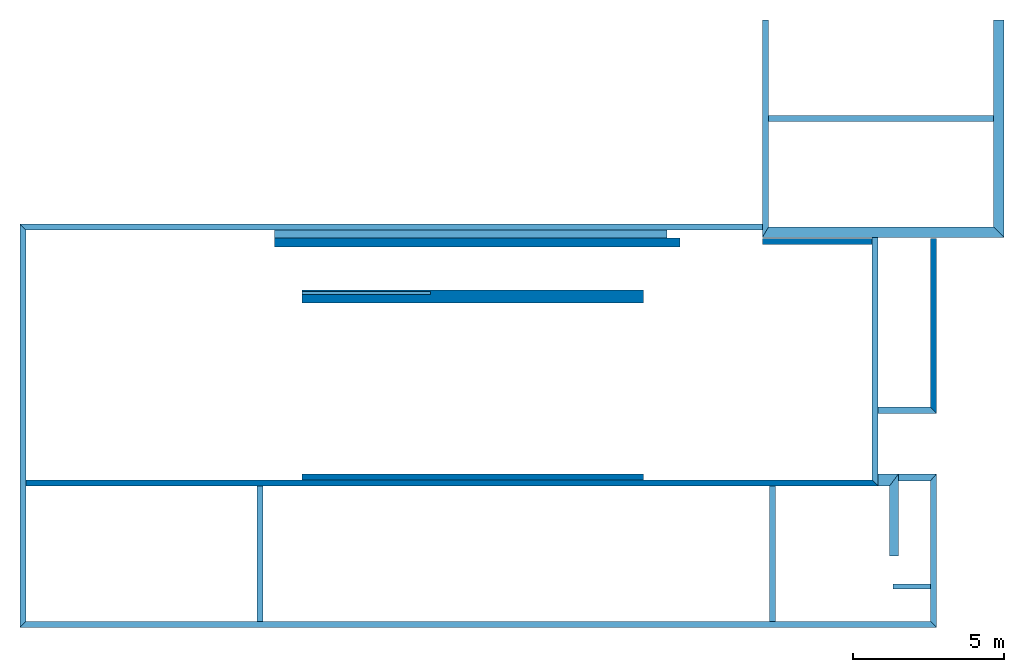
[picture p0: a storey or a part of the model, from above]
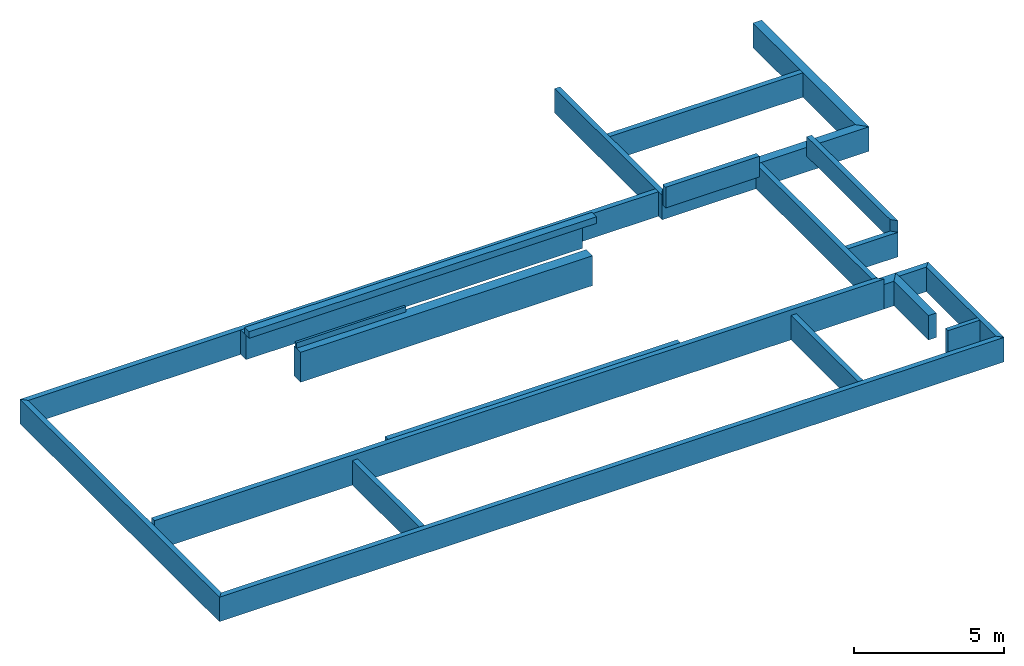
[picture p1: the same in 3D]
Properties of the parts of a building model (IFC2X3)

# File
Description: ViewDefinition [CoordinationView_V2.0], Option [Elements to export: Entire project], Option [Partial Structure Display: Entire Model], Option [IFC Domain: All], Option [Structural Function: All Elements], Option [Convert Grid elements: On], Option [Convert IFC Annotations and ARCHICAD 2D elements: Off], Option [Convert 2D symbols of Doors and Windows: Off], Option [Export geometries that Participates in Collision Detection only: Off], Option [Split complex elements: Off], Option [Material Preservation: Explode where necessary], Option [Elements in Solid Element Operations: Extruded/revolved], Option [Elements with junctions: Extruded/revolved without junctions], Option [IFC Model position: Survey Point and Project Origin], Option [Curtain Wall export mode: Container Element], Option [Railing export mode: Single Element], Option [Stair export mode: Container Element], Option [Properties To Export: All properties], Option [Space containment: Off], Option [Bounding Box: Off], Option [Geometry to type objects: Off], Option [Element Properties: Off], Option [Building Material Properties: Off], Option [Element Parameters: Off], Option [Component Parameters: Off], Option [IFC Base Quantities: Off], Option [Door Window Parameters: Off], Option [IFC Space boundaries: Off], Option [ARCHICAD Zone Categories as IFC Space classification data: Off], Option [Element Classifications: On]
File name: /Users/adquat/Desktop/SAUV/9 EGLISE SDFPRO DCE.ifc
Time: 2024-02-08T12:19:42
Author: (nom de l'architecte)
Organization: (Atelier d'architecture.... )
Written by: The EXPRESS Data Manager Version 5.02.0100.09 : 18 Aug 2016
Made in: IFC file generated by GRAPHISOFT ARCHICAD 25.0.0 FRA FULL Macintosh version (IFC add-on version: 4013 FRA FULL).
Authorization: (nom de l'architecte)

# IfcProject, SALLE DES FÈTES DE NEUF ÉGLISE
Phase: EDL

# IfcSite, Site
RefLatitude: 48, 52, 0, 0; RefLongitude: 2, 20, 0, 0; RefElevation: 0 m

# IfcBuildingStorey (4)
In: Bâtiment
Name | Elevation (m)
VIDE SANITAIRE | -1
RDC | -5.32907e-15
PLAFOND | 4
TOITURE | 7.4

# IfcSpace: 9 Communication & Accès (16)
In: RDC
InteriorOrExteriorSpace: INTERNAL; Classification: Espace (Classification ARCHICAD)
AC_Pset_RenovationAndPhasing - Renovation Status: Existing
Name (Plafond:...) | LongName
 Dalles | VESTIAIRE
 Dalles | SALLE PRINCIPALE
 Dalles | ACCUEIL
 Ba CF1h | RANGEMENT
 Dalles | DGT.
 BA cf1h | L. TECH.-REGIE
 Ba CF1H | STOCKAGE
 Dalles | SAN. H
 Dalles | Mixte PMR
 Dalles | DEGT.
 Dalles | Public PMR
 Dalles | CUISINE
 Dalles | L.Tech
 Dalles | SAN. F
 Dalles | BUVETTE
 Dalles

# IfcBuildingElementPart (10)
In: RDC
Name | Material
5 x Plâtre lissé 291446788 | Plâtre lissé 291446788
5 x Isolation laine de pierre 378182646 | Isolation laine de pierre 378182646

# IfcBuildingElementProxy: IfcBuildingElementProxy, MARCHE-012
In: RDC
Material: Bois 390117389
AC_Pset_RenovationAndPhasing - Renovation Status: New

# IfcBuildingElementProxy: Type d'escalier, ESCALIER-003
In: RDC
AC_Pset_RenovationAndPhasing - Renovation Status: New

# IfcColumn: Diagonales 1167258944 150 x 150 (2)
In: RDC
Classification: Poteau (Classification ARCHICAD); Material: Diagonales 1167258944
AC_Pset_RenovationAndPhasing - Renovation Status: New
Pset_ColumnCommon - LoadBearing: yes; IsExternal: no; Reference: Diagonales 1167258944 150 x 150

# IfcColumn: Diagonales 1167258944 200 x 200 (2)
In: RDC
Classification: Poteau (Classification ARCHICAD); Material: Diagonales 1167258944
Pset_ColumnCommon - LoadBearing: yes; IsExternal: no; Reference: Diagonales 1167258944 200 x 200
Name | Renovation Status
Pot-003 | To Be Demolished
Pot-002 | New

# IfcColumn: Diagonales 1167258944 D180 (3)
In: RDC
Classification: Poteau (Classification ARCHICAD); Material: Diagonales 1167258944
AC_Pset_RenovationAndPhasing - Renovation Status: To Be Demolished
Pset_ColumnCommon - LoadBearing: yes; IsExternal: no; Reference: Diagonales 1167258944 D180

# IfcDiscreteAccessory: Chevron simple 25 (15)
In: TOITURE
Classification: Accessoire distinct (Classification ARCHICAD); Material: Béton 2389403790
AC_Pset_RenovationAndPhasing - Renovation Status: New

# IfcDiscreteAccessory: Panne 25 (28)
In: TOITURE
Classification: Accessoire distinct (Classification ARCHICAD); Material: Béton 2389403790
AC_Pset_RenovationAndPhasing - Renovation Status: New
Name
14 x Protection-014
14 x Protection-012

# IfcDiscreteAccessory: Poteau 1 25 (7)
In: TOITURE
Classification: Accessoire distinct (Classification ARCHICAD); Material: Béton 2389403790
AC_Pset_RenovationAndPhasing - Renovation Status: New

# IfcDistributionElement: Evier à double bacs 25 (2)
In: RDC
Classification: Élément de distribution (Classification ARCHICAD)
Name | Renovation Status
Protection-003 | Existing
Protection-003 | New

# IfcDistributionElement: Lavabo 25, Protection-011
In: RDC
Classification: Élément de distribution (Classification ARCHICAD)
AC_Pset_RenovationAndPhasing - Renovation Status: New

# IfcDistributionElement: Lavabo d'angle 25 (2)
In: RDC
Classification: Élément de distribution (Classification ARCHICAD)
AC_Pset_RenovationAndPhasing - Renovation Status: New

# IfcDistributionElement: Plan multi vasques 25, Protection-011
In: RDC
Classification: Élément de distribution (Classification ARCHICAD)
AC_Pset_RenovationAndPhasing - Renovation Status: New

# IfcDistributionElement: Urinoir 25 (2)
In: RDC
Classification: Élément de distribution (Classification ARCHICAD)
AC_Pset_RenovationAndPhasing - Renovation Status: New

# IfcDistributionElement: WC 25 (4)
In: RDC
Classification: Élément de distribution (Classification ARCHICAD)
AC_Pset_RenovationAndPhasing - Renovation Status: New

# IfcDoor: Porte 25 (5)
In: RDC
Type - OperationType: SINGLE_SWING_LEFT; ParameterTakesPrecedence: no; Sizeable: no
Classification: Porte (Classification ARCHICAD)
Name | OverallHeight (m) | OverallWidth (m) | Renovation Status
Por-004 | 2.1 | 0.91 | New
Por-004 | 2.1 | 1.086 | New
Por-005 | 2.13 | 0.91 | Existing
Por-004 | 2.118 | 0.886 | New
Por-004 | 2.1 | 0.596 | New

# IfcDoor: Porte 25 (7)
In: RDC
Type - OperationType: SINGLE_SWING_RIGHT; ParameterTakesPrecedence: no; Sizeable: no
Classification: Porte (Classification ARCHICAD)
AC_Pset_RenovationAndPhasing - Renovation Status: New
Name | OverallHeight (m) | OverallWidth (m)
Por-004 | 2.1 | 0.8
Por-004 | 2.1 | 0.886
2 x Por-004 | 2.1 | 1.086
Por-006 | 2.1 | 0.6
Por-006 | 2.1 | 0.733967
Por-004 | 2.118 | 0.886

# IfcDoor: Porte avec imposte 25, Por-004
In: RDC
Type - OperationType: SINGLE_SWING_RIGHT; ParameterTakesPrecedence: no; Sizeable: no
OverallHeight: 2.5 m; OverallWidth: 1.03 m; Classification: Porte (Classification ARCHICAD)
AC_Pset_RenovationAndPhasing - Renovation Status: New

# IfcDoor: Porte double 25 (2)
In: RDC
Type - OperationType: DOUBLE_DOOR_SINGLE_SWING; ParameterTakesPrecedence: no; Sizeable: no
Classification: Porte (Classification ARCHICAD)
AC_Pset_RenovationAndPhasing - Renovation Status: Existing
Name | OverallHeight (m) | OverallWidth (m)
Por-006 | 2.1 | 1.8
Por-006 | 2.5 | 2.34

# IfcDoor: Porte double asymétrique 25, Por-006
In: RDC
Type - OperationType: DOUBLE_DOOR_DOUBLE_SWING; ParameterTakesPrecedence: no; Sizeable: no
OverallHeight: 2.1 m; OverallWidth: 1.48 m; Classification: Porte (Classification ARCHICAD)
AC_Pset_RenovationAndPhasing - Renovation Status: New

# IfcDoor: Porte double asymétrique 25 (5)
In: RDC
Type - OperationType: DOUBLE_DOOR_SINGLE_SWING; ParameterTakesPrecedence: no; Sizeable: no
Classification: Porte (Classification ARCHICAD)
AC_Pset_RenovationAndPhasing - Renovation Status: New
Name | OverallHeight (m) | OverallWidth (m)
Por-006 | 2.1 | 1.5
2 x Por-006 | 2.1 | 1.47
Por-006 | 2.1 | 1.4
Por-006 | 2.15 | 1.3

# IfcFurnishingElement: Cuisinière gaz 25, Protection-003
In: RDC
Classification: Mobilier (Classification ARCHICAD)
AC_Pset_RenovationAndPhasing - Renovation Status: Existing

# IfcSlab: 50 % 1167783752 28, Dalle-16
In: RDC
Type - PredefinedType: FLOOR
Classification: Dalle (Classification ARCHICAD); Material: 50 % 1167783752 0.028 m
AC_Pset_RenovationAndPhasing - Renovation Status: New

# IfcSlab: 50 % 1167783752 30 (3)
In: RDC
Type - PredefinedType: FLOOR
Classification: Dalle (Classification ARCHICAD); Material: 50 % 1167783752 0.03 m
AC_Pset_RenovationAndPhasing - Renovation Status: New

# IfcSlab: 50 % 1167783752 50 (6)
In: RDC
Type - PredefinedType: FLOOR
Classification: Dalle (Classification ARCHICAD); Material: 50 % 1167783752 0.05 m
AC_Pset_RenovationAndPhasing - Renovation Status: New
Name
3 x Dalle-13
Dalle-17
2 x Dalle-16

# IfcSlab: Dalle: Etancheite bicouche auto protegee + iso22 375 (3)
In: TOITURE
Type - PredefinedType: FLOOR
Classification: Dalle (Classification ARCHICAD); Material: Fer 269029580 0.005 m, Etanchéité 286798990 0.005 m, 25 % 7019220 0.005 m, Isolation laine de pierre 356123750 0.15 m, 50 % 1167783752 0.005 m, Sans Trame 1167258944 0.005 m, Bois massif 333501804 0.2 m
AC_Pset_RenovationAndPhasing - Renovation Status: New

# IfcSlab: Diagonales 1167258944 200 (2)
In: RDC
Type - PredefinedType: FLOOR
Classification: Dalle (Classification ARCHICAD); Material: Diagonales 1167258944 0.2 m
Name | Renovation Status
Dalle-13 | To Be Demolished
Dalle-13 | New

# IfcSlab: SDF TOITURE 16 160 (4)
In: PLAFOND
Type - PredefinedType: ROOF
Classification: Toit (Classification ARCHICAD); Material: Sans Trame 289679044 0.05 m, Lame d'air 294416412 0.1 m, Sans Trame 1167258944 0.01 m
Pset_SlabCommon - LoadBearing: no; IsExternal: yes
Name | Renovation Status
2 x Toit-02 | New
2 x Toit-02 | To Be Demolished

# IfcSlab: Sans Trame 1167258944 1080, Dalle-16
In: RDC
Type - PredefinedType: FLOOR
Classification: Dalle (Classification ARCHICAD); Material: Sans Trame 1167258944 1.08 m
AC_Pset_RenovationAndPhasing - Renovation Status: To Be Demolished

# IfcSlab: Sans Trame 1167258944 1260, Dalle-15
In: RDC
Type - PredefinedType: FLOOR
Classification: Dalle (Classification ARCHICAD); Material: Sans Trame 1167258944 1.26 m
AC_Pset_RenovationAndPhasing - Renovation Status: To Be Demolished

# IfcSlab: Sans Trame 1167258944 153 (2)
In: PLAFOND
Type - PredefinedType: ROOF
Classification: Toit (Classification ARCHICAD); Material: Sans Trame 1167258944 0.153252 m
AC_Pset_RenovationAndPhasing - Renovation Status: Existing
Pset_SlabCommon - LoadBearing: no; IsExternal: yes

# IfcSlab: Sans Trame 1167258944 160 (2)
In: RDC
Type - PredefinedType: FLOOR
Classification: Dalle (Classification ARCHICAD)
Name | Material | Renovation Status
Dalle-17 | Sans Trame 1167258944 0.160473 m | To Be Demolished
Dalle-14 | Sans Trame 1167258944 0.16 m | Existing

# IfcSlab: Sans Trame 1167258944 180, Dalle-17
In: RDC
Type - PredefinedType: FLOOR
Classification: Dalle (Classification ARCHICAD); Material: Sans Trame 1167258944 0.18 m
AC_Pset_RenovationAndPhasing - Renovation Status: Existing

# IfcSlab: Sans Trame 1167258944 200 (6)
In: RDC
Type - PredefinedType: FLOOR
Classification: Dalle (Classification ARCHICAD); Material: Sans Trame 1167258944 0.2 m
AC_Pset_RenovationAndPhasing - Renovation Status: Existing
Name
3 x Dalle-23
2 x Dalle-16
Dalle-13

# IfcSlab: Sans Trame 1167258944 250, Dalle-15
In: RDC
Type - PredefinedType: FLOOR
Classification: Dalle (Classification ARCHICAD); Material: Sans Trame 1167258944 0.25 m
AC_Pset_RenovationAndPhasing - Renovation Status: To Be Demolished

# IfcSlab: Sans Trame 1167258944 28 (2)
In: RDC
Type - PredefinedType: FLOOR
Classification: Dalle (Classification ARCHICAD); Material: Sans Trame 1167258944 0.028 m
AC_Pset_RenovationAndPhasing - Renovation Status: New
Name
Dalle-16
Dalle-22

# IfcSlab: Sans Trame 1167258944 30 (7)
In: RDC
Type - PredefinedType: FLOOR
Classification: Dalle (Classification ARCHICAD); Material: Sans Trame 1167258944 0.03 m
AC_Pset_RenovationAndPhasing - Renovation Status: New
Name
5 x Dalle-13
Dalle-14
Dalle-22

# IfcSlab: Sans Trame 1167258944 331, Dalle-17
In: RDC
Type - PredefinedType: FLOOR
Classification: Dalle (Classification ARCHICAD); Material: Sans Trame 1167258944 0.330947 m
AC_Pset_RenovationAndPhasing - Renovation Status: To Be Demolished

# IfcSlab: Sans Trame 1167258944 400, Dalle-19
In: RDC
Type - PredefinedType: FLOOR
Classification: Dalle (Classification ARCHICAD); Material: Sans Trame 1167258944 0.4 m
AC_Pset_RenovationAndPhasing - Renovation Status: New

# IfcSlab: Sans Trame 1167258944 470, Dalle-24
In: RDC
Type - PredefinedType: FLOOR
Classification: Dalle (Classification ARCHICAD); Material: Sans Trame 1167258944 0.47 m
AC_Pset_RenovationAndPhasing - Renovation Status: Existing

# IfcSlab: Sans Trame 1167258944 50 (4)
Type - PredefinedType: FLOOR
Classification: Dalle (Classification ARCHICAD); Material: Sans Trame 1167258944 0.05 m
Name | In | Renovation Status
2 x Dalle-14 | RDC | New
2 x Dalle-13 | PLAFOND | Existing

# IfcSlab: Sans Trame 1167258944 900, Dalle-17
In: RDC
Type - PredefinedType: FLOOR
Classification: Dalle (Classification ARCHICAD); Material: Sans Trame 1167258944 0.9 m
AC_Pset_RenovationAndPhasing - Renovation Status: To Be Demolished

# IfcWall: DOUBLAGE ISO + BA13 10 CM 100 (5)
In: RDC
Classification: Mur (Classification ARCHICAD)
AC_Pset_RenovationAndPhasing - Renovation Status: Existing
Name
Mur-007
Mur-006
Mur-009
Mur-008
Mur-005

# IfcWall: Diagonales 1167258944 200 (2)
In: RDC
Classification: Mur (Classification ARCHICAD); Material: Diagonales 1167258944
AC_Pset_RenovationAndPhasing - Renovation Status: Existing

# IfcWall: Diagonales 1167258944 340, Mur-005
In: RDC
Classification: Mur (Classification ARCHICAD); Material: Diagonales 1167258944
AC_Pset_RenovationAndPhasing - Renovation Status: Existing

# IfcWall: Plâtre cloisons 1818619258 30, Mur-010
In: RDC
Classification: Mur (Classification ARCHICAD); Material: Plâtre cloisons 1818619258
AC_Pset_RenovationAndPhasing - Renovation Status: New

# IfcWallStandardCase: 50 % 1167783752 10 (2)
In: RDC
Classification: Mur (Classification ARCHICAD); Material: 50 % 1167783752 0.01 m
AC_Pset_RenovationAndPhasing - Renovation Status: New

# IfcWallStandardCase: 50 % 1167783752 20 (2)
In: RDC
Classification: Mur (Classification ARCHICAD); Material: 50 % 1167783752 0.02 m
AC_Pset_RenovationAndPhasing - Renovation Status: New

# IfcWallStandardCase: 50 % 1167783752 200 (3)
Classification: Mur (Classification ARCHICAD); Material: 50 % 1167783752 0.2 m
AC_Pset_RenovationAndPhasing - Renovation Status: New
Name | In
Mur-004 | VIDE SANITAIRE
Mur-004 | PLAFOND
Mur-005 | PLAFOND

# IfcWallStandardCase: 50 % 1167783752 30 (3)
In: RDC
Classification: Mur (Classification ARCHICAD); Material: 50 % 1167783752 0.03 m
AC_Pset_RenovationAndPhasing - Renovation Status: New
Name
Mur-011
Mur-012
Mur-016

# IfcWallStandardCase: CLOISON 10 81 (3)
Classification: Mur (Classification ARCHICAD); Material: Plâtre lissé 291446788 0.018 m, Isolation laine de pierre 307970822 0.045 m, Plâtre lissé 291446788 0.018 m
AC_Pset_RenovationAndPhasing - Renovation Status: New
Name | In
2 x Mur-010 | RDC
Mur-010 | PLAFOND

# IfcWallStandardCase: CLOISON 10 ROUGE 100 (17)
In: RDC
Classification: Mur (Classification ARCHICAD); Material: Plâtre lissé 291446788 0.015 m, Isolation laine de pierre 307970822 0.07 m, Plâtre lissé 291446788 0.015 m
AC_Pset_RenovationAndPhasing - Renovation Status: New
Name
16 x Mur-010
Mur-011

# IfcWallStandardCase: CLOISON 84/45 iso 81 (6)
In: RDC
Classification: Mur (Classification ARCHICAD); Material: Plâtre lissé 291446788 0.018 m, Isolation laine de pierre 378641718 0.045 m, Plâtre lissé 291446788 0.018 m
Name | Renovation Status
2 x Mur-005 | To Be Demolished
2 x Mur-010 | New
Mur-006 | To Be Demolished
Mur-013 | To Be Demolished

# IfcWallStandardCase: Cloison: Gaine TECH 72/45 70 (4)
In: RDC
Classification: Mur (Classification ARCHICAD); Material: Plâtre lissé 291446788 0.027 m, Isolation laine de pierre 307970822 0.032 m, Plâtre lissé 291446788 0.0113 m
AC_Pset_RenovationAndPhasing - Renovation Status: New
Name
3 x Mur-010
Mur-011

# IfcWallStandardCase: DOUBLAGE ISO + BA13 10 CM ROUGE 100, Mur-006
In: RDC
Classification: Mur (Classification ARCHICAD); Material: Isolation laine de pierre 378182646 0.08 m, Plâtre lissé 291446788 0.02 m
AC_Pset_RenovationAndPhasing - Renovation Status: New

# IfcWallStandardCase: DOUBLAGE ISO + BA13 14 CM 140 (16)
In: RDC
Classification: Mur (Classification ARCHICAD); Material: Isolation laine de pierre 378182646 0.12 m, Plâtre lissé 291446788 0.02 m
AC_Pset_RenovationAndPhasing - Renovation Status: New
Name
6 x Mur-006
4 x Mur-005
2 x Mur-003
3 x Mur-004
Mur-002

# IfcWallStandardCase: Diagonales 1167258944 150 (2)
In: RDC
Classification: Mur (Classification ARCHICAD); Material: Diagonales 1167258944 0.15 m
AC_Pset_RenovationAndPhasing - Renovation Status: To Be Demolished

# IfcWallStandardCase: Diagonales 1167258944 170 (2)
Classification: Mur (Classification ARCHICAD); Material: Diagonales 1167258944 0.17 m
Name | In | Renovation Status
Mur-007 | VIDE SANITAIRE | Existing
Mur-005 | RDC | To Be Demolished

# IfcWallStandardCase: Diagonales 1167258944 180 (5)
In: RDC
Classification: Mur (Classification ARCHICAD); Material: Diagonales 1167258944 0.18 m
Name | Renovation Status
4 x Mur-002 | To Be Demolished
Mur-002 | Existing

# IfcWallStandardCase: Diagonales 1167258944 190 (10)
In: RDC
Classification: Mur (Classification ARCHICAD); Material: Diagonales 1167258944 0.19 m
AC_Pset_RenovationAndPhasing - Renovation Status: Existing
Name
Mur-011
Mur-006
2 x Mur-008
2 x Mur-009
2 x Mur-013
Mur-007
Mur-012

# IfcWallStandardCase: Diagonales 1167258944 200 (35)
Classification: Mur (Classification ARCHICAD); Material: Diagonales 1167258944 0.2 m
Name | In | Renovation Status
2 x Mur-006 | VIDE SANITAIRE | Existing
4 x Mur-003 | VIDE SANITAIRE | Existing
3 x Mur-004 | VIDE SANITAIRE | Existing
2 x Mur-005 | VIDE SANITAIRE | Existing
2 x Mur-004 | VIDE SANITAIRE | New
Mur-009 | RDC | Existing
Mur-004 | RDC | Existing
2 x Mur-002 | RDC | To Be Demolished
3 x Mur-006 | RDC | Existing
2 x Mur-005 | RDC | To Be Demolished
Mur-007 | RDC | Existing
3 x Mur-005 | RDC | Existing
3 x Mur-002 | RDC | Existing
Mur-004 | PLAFOND | Existing
2 x Mur-008 | TOITURE | New
2 x Mur-006 | TOITURE | New
Mur-007 | TOITURE | New

# IfcWallStandardCase: Diagonales 1167258944 230 (2)
Classification: Mur (Classification ARCHICAD); Material: Diagonales 1167258944 0.23 m
AC_Pset_RenovationAndPhasing - Renovation Status: Existing
Name | In
Mur-005 | VIDE SANITAIRE
Mur-010 | RDC

# IfcWallStandardCase: Diagonales 1167258944 260 (2)
In: RDC
Classification: Mur (Classification ARCHICAD); Material: Diagonales 1167258944 0.26 m
AC_Pset_RenovationAndPhasing - Renovation Status: Existing

# IfcWallStandardCase: Diagonales 1167258944 300 (4)
Classification: Mur (Classification ARCHICAD); Material: Diagonales 1167258944 0.3 m
Name | In | Renovation Status
Mur-006 | VIDE SANITAIRE | Existing
Mur-003 | VIDE SANITAIRE | Existing
Mur-008 | RDC | Existing
Mur-008 | RDC | To Be Demolished

# IfcWallStandardCase: Diagonales 1167258944 340 (3)
Classification: Mur (Classification ARCHICAD); Material: Diagonales 1167258944 0.34 m
AC_Pset_RenovationAndPhasing - Renovation Status: Existing
Name | In
Mur-005 | VIDE SANITAIRE
Mur-006 | VIDE SANITAIRE
Mur-004 | RDC

# IfcWallStandardCase: Diagonales 1167258944 400 (4)
Classification: Mur (Classification ARCHICAD); Material: Diagonales 1167258944 0.4 m
AC_Pset_RenovationAndPhasing - Renovation Status: Existing
Name | In
Mur-005 | VIDE SANITAIRE
Mur-002 | RDC
Mur-003 | RDC
Mur-010 | RDC

# IfcWallStandardCase: Diagonales 1167258944 420, Mur-003
In: VIDE SANITAIRE
Classification: Mur (Classification ARCHICAD); Material: Diagonales 1167258944 0.42 m
AC_Pset_RenovationAndPhasing - Renovation Status: Existing

# IfcWallStandardCase: Diagonales 1167258944 550, Mur-003
In: VIDE SANITAIRE
Classification: Mur (Classification ARCHICAD); Material: Diagonales 1167258944 0.55 m
AC_Pset_RenovationAndPhasing - Renovation Status: Existing

# IfcWallStandardCase: Diagonales 1167258944 90, Mur-003
In: VIDE SANITAIRE
Classification: Mur (Classification ARCHICAD); Material: Diagonales 1167258944 0.09 m
AC_Pset_RenovationAndPhasing - Renovation Status: Existing

# IfcWallStandardCase: Mur: béton + enduit 240 (3)
Classification: Mur (Classification ARCHICAD); Material: Sans Trame 1167258944 0.02 m, Diagonales 1167258944 0.2 m, Sans Trame 1167258944 0.02 m
AC_Pset_RenovationAndPhasing - Renovation Status: New
Name | In
2 x Mur-010 | PLAFOND
Mur-007 | TOITURE

# IfcWallStandardCase: Mur: béton + isolant + revêt int 373 (2)
In: RDC
Classification: Mur (Classification ARCHICAD); Material: Sans Trame 1167258944 0.02 m, 50 % 1167783752 0.2 m, Isolation laine de pierre 378182646 0.14 m, Plâtre lissé 291446788 0.013 m
AC_Pset_RenovationAndPhasing - Renovation Status: New

# IfcWallStandardCase: Mur: béton + isolant 353 (2)
In: RDC
Classification: Mur (Classification ARCHICAD); Material: 50 % 1167783752 0.2 m, Isolation laine de pierre 378182646 0.14 m, Plâtre lissé 291446788 0.013 m
AC_Pset_RenovationAndPhasing - Renovation Status: New

# IfcWallStandardCase: Métal 368073405 20 (29)
In: RDC
Classification: Mur (Classification ARCHICAD); Material: Métal 368073405 0.02 m
AC_Pset_RenovationAndPhasing - Renovation Status: New

# IfcWallStandardCase: Plâtre cloisons 1818619258 10 (2)
In: RDC
Classification: Mur (Classification ARCHICAD); Material: Plâtre cloisons 1818619258 0.01 m
AC_Pset_RenovationAndPhasing - Renovation Status: New

# IfcWallStandardCase: Plâtre cloisons 1818619258 20 (4)
In: RDC
Classification: Mur (Classification ARCHICAD); Material: Plâtre cloisons 1818619258 0.02 m
AC_Pset_RenovationAndPhasing - Renovation Status: To Be Demolished
Name
2 x Mur-006
2 x Mur-005

# IfcWallStandardCase: Plâtre cloisons 1818619258 30 (21)
In: RDC
Classification: Mur (Classification ARCHICAD); Material: Plâtre cloisons 1818619258 0.03 m
AC_Pset_RenovationAndPhasing - Renovation Status: New
Name
3 x Mur-012
7 x Mur-015
4 x Mur-010
3 x Mur-011
2 x Mur-013
Mur-014
Mur-017

# IfcWallStandardCase: Plâtre cloisons 1818619258 50 (3)
In: RDC
Classification: Mur (Classification ARCHICAD); Material: Plâtre cloisons 1818619258 0.05 m
AC_Pset_RenovationAndPhasing - Renovation Status: New
Name
Mur-010
2 x Mur-015

# IfcWindow: Fenêtre 25 (2)
In: RDC
Type - OperationType: SINGLE_PANEL; ParameterTakesPrecedence: no; Sizeable: no
Classification: Fenêtre (Classification ARCHICAD)
AC_Pset_RenovationAndPhasing - Renovation Status: Existing
Name | OverallHeight (m) | OverallWidth (m)
Fen-012 | 2.1 | 1.35
Fen-010 | 0.62 | 0.59

# IfcWindow: Fenêtre châssis double 25 (10)
In: RDC
Type - OperationType: DOUBLE_PANEL_VERTICAL; ParameterTakesPrecedence: no; Sizeable: no
OverallHeight: 1.08 m; Classification: Fenêtre (Classification ARCHICAD)
Name | OverallWidth (m) | Renovation Status
2 x Fen-003 | 1.23 | Existing
Fen-005 | 1.23 | Existing
6 x Fen-003 | 1.257 | New
Fen-003 | 0.91 | New

# IfcWindow: Fenêtre châssis double 25 (4)
In: RDC
Type - OperationType: TRIPLE_PANEL_BOTTOM; ParameterTakesPrecedence: no; Sizeable: no
OverallHeight: 1.82 m; OverallWidth: 1 m; Classification: Fenêtre (Classification ARCHICAD)
AC_Pset_RenovationAndPhasing - Renovation Status: New
Name
3 x Fen-003
Fen-004

# IfcWindow: Fenêtre châssis double variable 25, Fen-009
In: RDC
Type - OperationType: TRIPLE_PANEL_BOTTOM; ParameterTakesPrecedence: no; Sizeable: no
OverallHeight: 2.13 m; OverallWidth: 1.76 m; Classification: Fenêtre (Classification ARCHICAD)
AC_Pset_RenovationAndPhasing - Renovation Status: Existing
